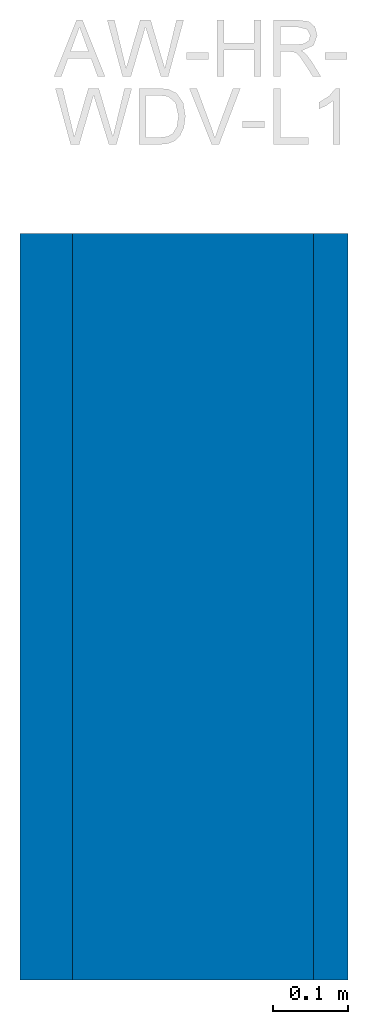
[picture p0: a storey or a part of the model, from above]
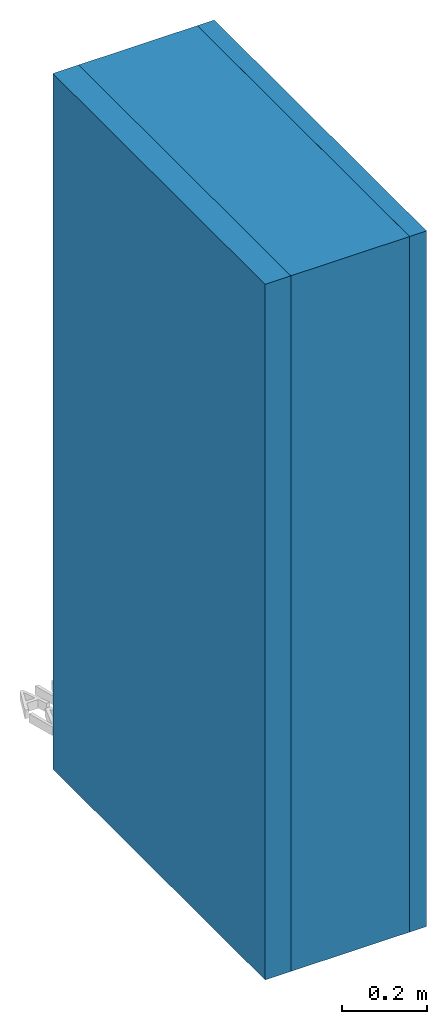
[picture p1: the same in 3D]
Properties of the parts of a building model (IFC4)

# File
Description: ViewDefinition [ReferenceView_V1.2], RevitIdentifiers [VersionGUID: 93d8a1e2-35a5-4253-ab7c-23872298a1db, NumberOfSaves: 0], CoordinateReference [CoordinateBase: Gemeinsam genutzte Koordinaten], ExchangeRequirement [Architecture]
File name: 2018_01
Time: 2023-06-27T14:28:09+01:00
Written by: ODA SDAI 23.12
Made in: Autodesk Revit 24.0.5.432 (DEU) - IFC 24.0.5.432

# IfcProject, 2018_01
Phase: Projekt Status

# IfcSite, Default
RefLatitude: 48, 8, 15, 359802; RefLongitude: 11, 34, 47, 783432; RefElevation: 0 m
Pset_SiteCommon - Reference: Projektinformationen

# IfcBuildingElementProxy: Modelltext:075mm Arial, Modelltext:075mm Arial:2509052
In: Default
Type - Pset_BuildingElementProxyCommon - IsExternal: no
Pset_BuildingElementProxyCommon - Reference: 075mm Arial
Pset_EnvironmentalImpactIndicators - Reference: 075mm Arial
Qto_BuildingElementProxyQuantities - NetSurfaceArea: 0.131073 m2; NetVolume: 0.000420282 m3

# IfcElementAssembly: Wände Baugruppe:fbimSg_Wall_bc_WOD_vis_at_NTR_natuREbuilt_AW-HR-WDV-L1_43,9cm, Wände Baugruppe:fbimSg_Wall_bc_WOD_vis_at_NTR_natuREbuilt_AW-HR-WDV-L1_43,9cm:2509056
In: Default
PredefinedType: USERDEFINED
Pset_ElementAssemblyCommon - Reference: fbimSg_Wall_bc_WOD_vis_at_NTR_natuREbuilt_AW-HR-WDV-L1_43,9cm; sets with these values: 2

# IfcWall: Basiswand:fbimSg_Wall_dp_PLA_vis_at_NTR_natuREbuilt_AWRv-l_Lopas1_i_4,6cm, Basiswand:fbimSg_Wall_dp_PLA_vis_at_NTR_natuREbuilt_AWRv-l_Lopas1_i_4,6cm:2509055
In: Default
Type - PredefinedType: STANDARD; Material: fbim_14100510_at_NTR_Hanffaserdaemmung, fbim_16200505_at_NTR_Lehm_Grundputz, fbim_16200510_at_NTR_Lehm_Duennputz
Type - Pset_WallCommon - IsExternal: no
Qto_WallBaseQuantities - fbim_14100510_at_NTR_Hanffaserdaemmung, Width: 0.001 m; fbim_16200505_at_NTR_Lehm_Grundputz, Width: 0.04 m; fbim_16200510_at_NTR_Lehm_Duennputz, Width: 0.005 m; Width: 0.046 m; Height: 2 m; Length: 1 m; GrossVolume: 0.092 m3; GrossSideArea: 2 m2; NetSideArea: 2 m2; NetVolume: 0.092 m3
Pset_EnvironmentalImpactIndicators - Reference: fbimSg_Wall_dp_PLA_vis_at_NTR_natuREbuilt_AWRv-l_Lopas1_i_4,6cm; sets with these values: 2
Pset_WallCommon - LoadBearing: no; ExtendToStructure: no; Reference: fbimSg_Wall_dp_PLA_vis_at_NTR_natuREbuilt_AWRv-l_Lopas1_i_4,6cm

# IfcWall: Basiswand:fbimSg_Wall_dp_WOD_vis_at_NTR_natuREbuilt_AWRv-l_Lopas1_a_7cm, Basiswand:fbimSg_Wall_dp_WOD_vis_at_NTR_natuREbuilt_AWRv-l_Lopas1_a_7cm:2509053
In: Default
Type - PredefinedType: STANDARD; Material: fbim_14153515_AT_001_Silikatputz_KP_1.5mm, fbim_14100530_AT_Holzfaserdaemmung
Type - Pset_WallCommon - IsExternal: no
Qto_WallBaseQuantities - fbim_14153515_AT_001_Silikatputz_KP_1.5mm, Width: 0.02 m; fbim_14100530_AT_Holzfaserdaemmung, Width: 0.05 m; Width: 0.07 m; Height: 2 m; Length: 1 m; GrossVolume: 0.14 m3; GrossSideArea: 2 m2; NetSideArea: 2 m2; NetVolume: 0.14 m3
Pset_EnvironmentalImpactIndicators - Reference: fbimSg_Wall_dp_WOD_vis_at_NTR_natuREbuilt_AWRv-l_Lopas1_a_7cm; sets with these values: 2
Pset_WallCommon - Reference: fbimSg_Wall_dp_WOD_vis_at_NTR_natuREbuilt_AWRv-l_Lopas1_a_7cm; LoadBearing: no; ExtendToStructure: no

# IfcWall: Basiswand:fbimSg_Wall_sb_WOD_vis_at_NTR_natuREbuilt_AWRv-l_Lopas1_k_32,3cm, Basiswand:fbimSg_Wall_sb_WOD_vis_at_NTR_natuREbuilt_AWRv-l_Lopas1_k_32,3cm:2509054
In: Default
Type - PredefinedType: STANDARD; Material: fbim_14100500_at_NTR_Strohdaemmung, fbim_12400515_AT_025_Vollholz_Bretter_Fichte
Type - Pset_WallCommon - IsExternal: no
Qto_WallBaseQuantities - fbim_14100500_at_NTR_Strohdaemmung, Width: 0.3 m; fbim_12400515_AT_025_Vollholz_Bretter_Fichte, Width: 0.023 m; Width: 0.323 m; Height: 2 m; Length: 1 m; GrossVolume: 0.646 m3; GrossSideArea: 2 m2; NetSideArea: 2 m2; NetVolume: 0.646 m3
Pset_EnvironmentalImpactIndicators - Reference: fbimSg_Wall_sb_WOD_vis_at_NTR_natuREbuilt_AWRv-l_Lopas1_k_32,3cm; sets with these values: 2
Pset_WallCommon - LoadBearing: no; ExtendToStructure: no; Reference: fbimSg_Wall_sb_WOD_vis_at_NTR_natuREbuilt_AWRv-l_Lopas1_k_32,3cm
